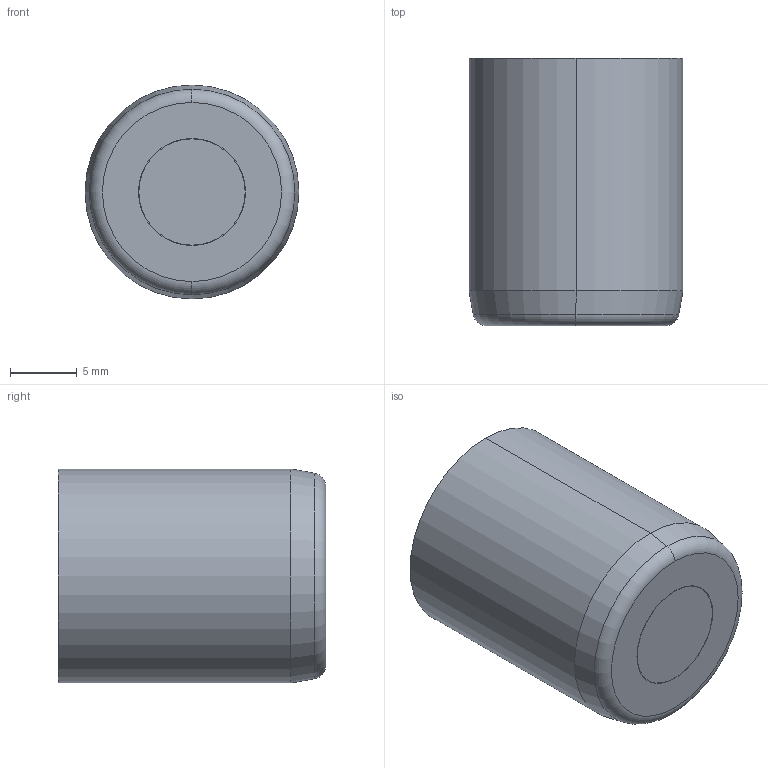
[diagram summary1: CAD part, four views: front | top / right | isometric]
STEP (ISO 10303-21) file: header records copied from the file, then geometry measured from it (millimetres).
FILE_DESCRIPTION (( 'STEP AP214' ), '1' );
FILE_NAME ('FA1687SF.STEP', '2013-06-28T08:04:21', ( '' ), ( '' ), 'SwSTEP 2.0', 'SolidWorks 2011', '' );
FILE_SCHEMA (( 'AUTOMOTIVE_DESIGN' ));
Length unit declared in the file: millimetre
Products named in the file (6): FA1687SF; 9FA 168712; FA 168700-2 comprimido; FA 168700-1; FA 168700-3; IA 8717SF
Assembly tree (5 placements, depth 2):
  FA1687SF
    FA 168700-2 comprimido
    FA 168700-3
    IA 8717SF
    FA 168700-1
    9FA 168712
Bounding box: 16 x 20 x 16 mm (x, y, z)
Volume: 3765 mm3; surface area: 2702.4 mm2
Topology: 5 solids, 5 shells, 312 faces, 790 edges, 513 vertices
Faces by surface type: plane 133, cylinder 133, cone 34, torus 10, bspline 2
Entity records: 10988 total; most frequent: CARTESIAN_POINT 2947, DIRECTION 1712, ORIENTED_EDGE 1576, EDGE_CURVE 788, AXIS2_PLACEMENT_3D 638, VERTEX_POINT 513, LINE 436, VECTOR 436
One B-rep face of a CAD part: STEP entity #88.
In plain terms, the cylindrical face has radius 8 mm (diameter 16 mm), a partial arc.
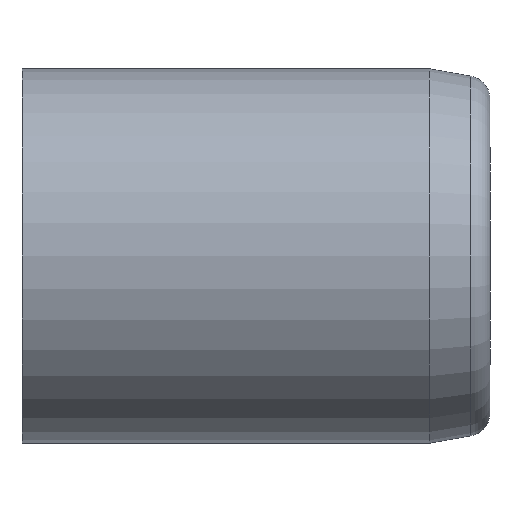
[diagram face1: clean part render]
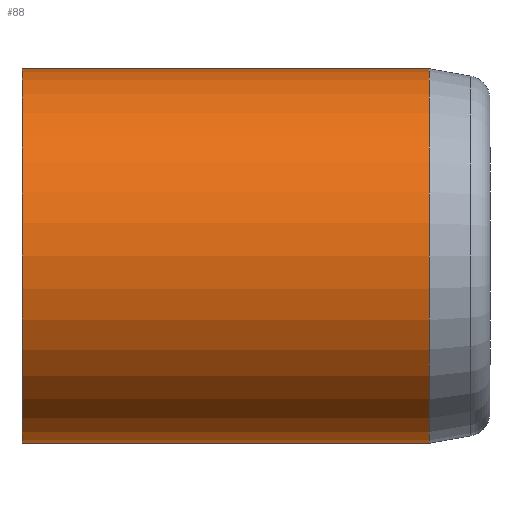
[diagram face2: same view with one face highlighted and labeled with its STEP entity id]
Its self-contained STEP definition (entity closure, numbers rounded to 3 decimals):
#88 = ADVANCED_FACE ( 'NONE', ( #4670 ), #4698, .T. ) ;
#1545 = AXIS2_PLACEMENT_3D ( 'NONE', #4693, #4663, #4671 ) ;
#2508 = CARTESIAN_POINT ( 'NONE',  ( 0., 2.73, -8. ) ) ;
#2585 = CARTESIAN_POINT ( 'NONE',  ( 0., 20.13, -8. ) ) ;
#2611 = CARTESIAN_POINT ( 'NONE',  ( 0., 20.13, 8. ) ) ;
#2620 = CARTESIAN_POINT ( 'NONE',  ( 0., 2.73, 8. ) ) ;
#3132 = EDGE_CURVE ( 'NONE', #8603, #8634, #5773, .T. ) ;
#3180 = EDGE_CURVE ( 'NONE', #8563, #8634, #8905, .T. ) ;
#3193 = EDGE_CURVE ( 'NONE', #8530, #8603, #8918, .T. ) ;
#3213 = EDGE_CURVE ( 'NONE', #8563, #8530, #5852, .T. ) ;
#3371 = AXIS2_PLACEMENT_3D ( 'NONE', #8999, #9041, #9028 ) ;
#3732 = EDGE_LOOP ( 'NONE', ( #8030, #8057, #8085, #8018 ) ) ;
#4663 = DIRECTION ( 'NONE',  ( 0., 1., 0. ) ) ;
#4670 = FACE_OUTER_BOUND ( 'NONE', #3732, .T. ) ;
#4671 = DIRECTION ( 'NONE',  ( 0., 0., 1. ) ) ;
#4693 = CARTESIAN_POINT ( 'NONE',  ( 0., -9.87, 0. ) ) ;
#4698 = CYLINDRICAL_SURFACE ( 'NONE', #1545, 8. ) ;
#5773 = CIRCLE ( 'NONE', #5802, 8. ) ;
#5802 = AXIS2_PLACEMENT_3D ( 'NONE', #10196, #10197, #10177 ) ;
#5807 = VECTOR ( 'NONE', #8914, 1000. ) ;
#5839 = VECTOR ( 'NONE', #8931, 1000. ) ;
#5852 = CIRCLE ( 'NONE', #3371, 8. ) ;
#8018 = ORIENTED_EDGE ( 'NONE', *, *, #3132, .F. ) ;
#8030 = ORIENTED_EDGE ( 'NONE', *, *, #3193, .F. ) ;
#8057 = ORIENTED_EDGE ( 'NONE', *, *, #3213, .F. ) ;
#8085 = ORIENTED_EDGE ( 'NONE', *, *, #3180, .T. ) ;
#8530 = VERTEX_POINT ( 'NONE', #2508 ) ;
#8563 = VERTEX_POINT ( 'NONE', #2620 ) ;
#8603 = VERTEX_POINT ( 'NONE', #2585 ) ;
#8634 = VERTEX_POINT ( 'NONE', #2611 ) ;
#8899 = CARTESIAN_POINT ( 'NONE',  ( 0., -9.87, 8. ) ) ;
#8905 = LINE ( 'NONE', #8899, #5807 ) ;
#8914 = DIRECTION ( 'NONE',  ( 0., 1., 0. ) ) ;
#8918 = LINE ( 'NONE', #8936, #5839 ) ;
#8931 = DIRECTION ( 'NONE',  ( 0., 1., 0. ) ) ;
#8936 = CARTESIAN_POINT ( 'NONE',  ( 0., -9.87, -8. ) ) ;
#8999 = CARTESIAN_POINT ( 'NONE',  ( 0., 2.73, 0. ) ) ;
#9028 = DIRECTION ( 'NONE',  ( 0., 0., -1. ) ) ;
#9041 = DIRECTION ( 'NONE',  ( 0., -1., 0. ) ) ;
#10177 = DIRECTION ( 'NONE',  ( 0., 0., 1. ) ) ;
#10196 = CARTESIAN_POINT ( 'NONE',  ( 0., 20.13, 0. ) ) ;
#10197 = DIRECTION ( 'NONE',  ( 0., 1., 0. ) ) ;
